VERSION 5.8 ;
BUSBITCHARS "[]" ;
DIVIDERCHAR "/" ;
UNITS
    DATABASE MICRONS 1000 ;
END UNITS

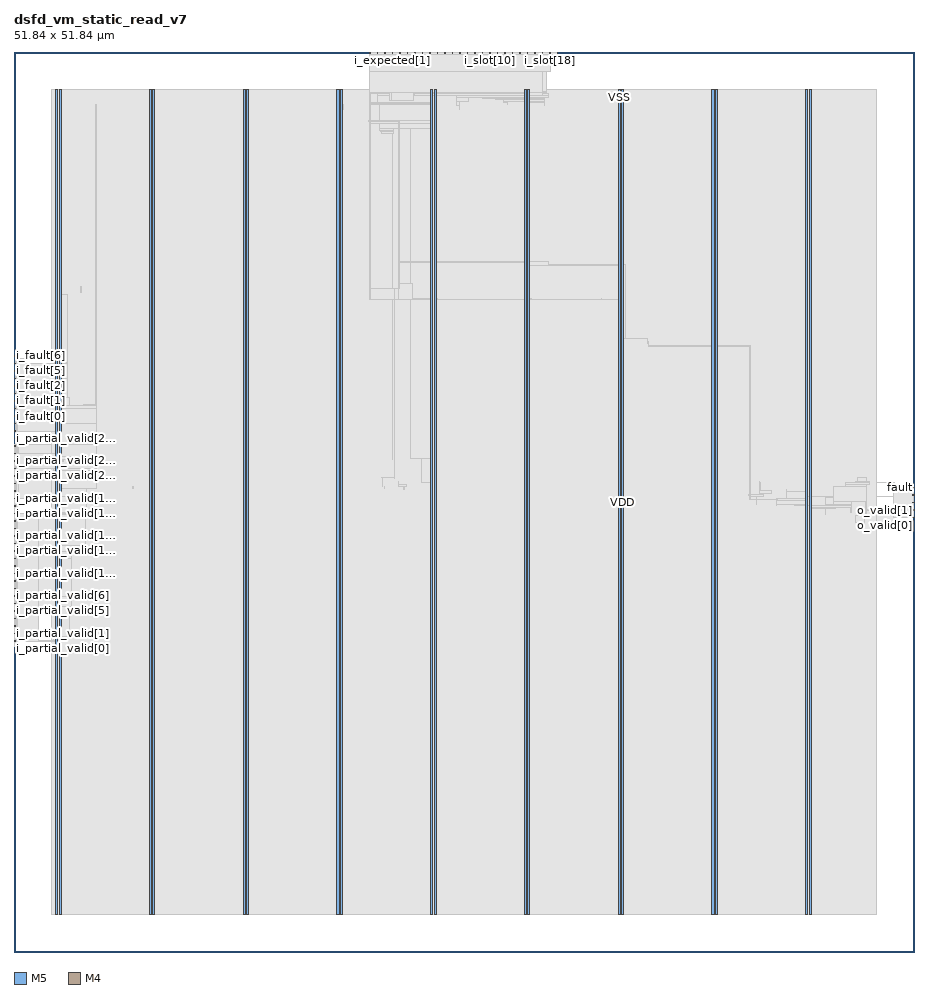
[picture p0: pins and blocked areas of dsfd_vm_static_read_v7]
MACRO dsfd_vm_static_read_v7
  FOREIGN dsfd_vm_static_read_v7 0 0 ;
  CLASS BLOCK ;
  SIZE 51.84 BY 51.84 ;
  PIN ck
    DIRECTION INPUT ;
    USE SIGNAL ;
    PORT
      LAYER M5 ;
        RECT  20.496 51.756 20.52 51.84 ;
    END
  END ck
  PIN fault
    DIRECTION OUTPUT ;
    USE SIGNAL ;
    PORT
      LAYER M4 ;
        RECT  51.756 26.736 51.84 26.76 ;
    END
  END fault
  PIN i_expected[0]
    DIRECTION INPUT ;
    USE SIGNAL ;
    PORT
      LAYER M5 ;
        RECT  21.36 51.756 21.384 51.84 ;
    END
  END i_expected[0]
  PIN i_expected[1]
    DIRECTION INPUT ;
    USE SIGNAL ;
    PORT
      LAYER M5 ;
        RECT  21.792 51.756 21.816 51.84 ;
    END
  END i_expected[1]
  PIN i_expected[2]
    DIRECTION INPUT ;
    USE SIGNAL ;
    PORT
      LAYER M5 ;
        RECT  22.224 51.756 22.248 51.84 ;
    END
  END i_expected[2]
  PIN i_expected[3]
    DIRECTION INPUT ;
    USE SIGNAL ;
    PORT
      LAYER M5 ;
        RECT  22.656 51.756 22.68 51.84 ;
    END
  END i_expected[3]
  PIN i_fault[0]
    DIRECTION INPUT ;
    USE SIGNAL ;
    PORT
      LAYER M4 ;
        RECT  0 31.296 0.084 31.32 ;
    END
  END i_fault[0]
  PIN i_fault[1]
    DIRECTION INPUT ;
    USE SIGNAL ;
    PORT
      LAYER M4 ;
        RECT  0 31.728 0.084 31.752 ;
    END
  END i_fault[1]
  PIN i_fault[2]
    DIRECTION INPUT ;
    USE SIGNAL ;
    PORT
      LAYER M4 ;
        RECT  0 32.16 0.084 32.184 ;
    END
  END i_fault[2]
  PIN i_fault[3]
    DIRECTION INPUT ;
    USE SIGNAL ;
    PORT
      LAYER M4 ;
        RECT  0 32.592 0.084 32.616 ;
    END
  END i_fault[3]
  PIN i_fault[4]
    DIRECTION INPUT ;
    USE SIGNAL ;
    PORT
      LAYER M4 ;
        RECT  0 33.024 0.084 33.048 ;
    END
  END i_fault[4]
  PIN i_fault[5]
    DIRECTION INPUT ;
    USE SIGNAL ;
    PORT
      LAYER M4 ;
        RECT  0 33.456 0.084 33.48 ;
    END
  END i_fault[5]
  PIN i_fault[6]
    DIRECTION INPUT ;
    USE SIGNAL ;
    PORT
      LAYER M4 ;
        RECT  0 33.888 0.084 33.912 ;
    END
  END i_fault[6]
  PIN i_fault[7]
    DIRECTION INPUT ;
    USE SIGNAL ;
    PORT
      LAYER M4 ;
        RECT  0 34.32 0.084 34.344 ;
    END
  END i_fault[7]
  PIN i_partial_valid[0]
    DIRECTION INPUT ;
    USE SIGNAL ;
    PORT
      LAYER M4 ;
        RECT  0 17.472 0.084 17.496 ;
    END
  END i_partial_valid[0]
  PIN i_partial_valid[10]
    DIRECTION INPUT ;
    USE SIGNAL ;
    PORT
      LAYER M4 ;
        RECT  0 21.792 0.084 21.816 ;
    END
  END i_partial_valid[10]
  PIN i_partial_valid[11]
    DIRECTION INPUT ;
    USE SIGNAL ;
    PORT
      LAYER M4 ;
        RECT  0 22.224 0.084 22.248 ;
    END
  END i_partial_valid[11]
  PIN i_partial_valid[12]
    DIRECTION INPUT ;
    USE SIGNAL ;
    PORT
      LAYER M4 ;
        RECT  0 22.656 0.084 22.68 ;
    END
  END i_partial_valid[12]
  PIN i_partial_valid[13]
    DIRECTION INPUT ;
    USE SIGNAL ;
    PORT
      LAYER M4 ;
        RECT  0 23.088 0.084 23.112 ;
    END
  END i_partial_valid[13]
  PIN i_partial_valid[14]
    DIRECTION INPUT ;
    USE SIGNAL ;
    PORT
      LAYER M4 ;
        RECT  0 23.52 0.084 23.544 ;
    END
  END i_partial_valid[14]
  PIN i_partial_valid[15]
    DIRECTION INPUT ;
    USE SIGNAL ;
    PORT
      LAYER M4 ;
        RECT  0 23.952 0.084 23.976 ;
    END
  END i_partial_valid[15]
  PIN i_partial_valid[16]
    DIRECTION INPUT ;
    USE SIGNAL ;
    PORT
      LAYER M4 ;
        RECT  0 24.384 0.084 24.408 ;
    END
  END i_partial_valid[16]
  PIN i_partial_valid[17]
    DIRECTION INPUT ;
    USE SIGNAL ;
    PORT
      LAYER M4 ;
        RECT  0 24.816 0.084 24.84 ;
    END
  END i_partial_valid[17]
  PIN i_partial_valid[18]
    DIRECTION INPUT ;
    USE SIGNAL ;
    PORT
      LAYER M4 ;
        RECT  0 25.248 0.084 25.272 ;
    END
  END i_partial_valid[18]
  PIN i_partial_valid[19]
    DIRECTION INPUT ;
    USE SIGNAL ;
    PORT
      LAYER M4 ;
        RECT  0 25.68 0.084 25.704 ;
    END
  END i_partial_valid[19]
  PIN i_partial_valid[1]
    DIRECTION INPUT ;
    USE SIGNAL ;
    PORT
      LAYER M4 ;
        RECT  0 17.904 0.084 17.928 ;
    END
  END i_partial_valid[1]
  PIN i_partial_valid[20]
    DIRECTION INPUT ;
    USE SIGNAL ;
    PORT
      LAYER M4 ;
        RECT  0 26.112 0.084 26.136 ;
    END
  END i_partial_valid[20]
  PIN i_partial_valid[21]
    DIRECTION INPUT ;
    USE SIGNAL ;
    PORT
      LAYER M4 ;
        RECT  0 26.544 0.084 26.568 ;
    END
  END i_partial_valid[21]
  PIN i_partial_valid[22]
    DIRECTION INPUT ;
    USE SIGNAL ;
    PORT
      LAYER M4 ;
        RECT  0 26.976 0.084 27 ;
    END
  END i_partial_valid[22]
  PIN i_partial_valid[23]
    DIRECTION INPUT ;
    USE SIGNAL ;
    PORT
      LAYER M4 ;
        RECT  0 27.408 0.084 27.432 ;
    END
  END i_partial_valid[23]
  PIN i_partial_valid[24]
    DIRECTION INPUT ;
    USE SIGNAL ;
    PORT
      LAYER M4 ;
        RECT  0 27.84 0.084 27.864 ;
    END
  END i_partial_valid[24]
  PIN i_partial_valid[25]
    DIRECTION INPUT ;
    USE SIGNAL ;
    PORT
      LAYER M4 ;
        RECT  0 28.272 0.084 28.296 ;
    END
  END i_partial_valid[25]
  PIN i_partial_valid[26]
    DIRECTION INPUT ;
    USE SIGNAL ;
    PORT
      LAYER M4 ;
        RECT  0 28.704 0.084 28.728 ;
    END
  END i_partial_valid[26]
  PIN i_partial_valid[27]
    DIRECTION INPUT ;
    USE SIGNAL ;
    PORT
      LAYER M4 ;
        RECT  0 29.136 0.084 29.16 ;
    END
  END i_partial_valid[27]
  PIN i_partial_valid[28]
    DIRECTION INPUT ;
    USE SIGNAL ;
    PORT
      LAYER M4 ;
        RECT  0 29.568 0.084 29.592 ;
    END
  END i_partial_valid[28]
  PIN i_partial_valid[29]
    DIRECTION INPUT ;
    USE SIGNAL ;
    PORT
      LAYER M4 ;
        RECT  0 30 0.084 30.024 ;
    END
  END i_partial_valid[29]
  PIN i_partial_valid[2]
    DIRECTION INPUT ;
    USE SIGNAL ;
    PORT
      LAYER M4 ;
        RECT  0 18.336 0.084 18.36 ;
    END
  END i_partial_valid[2]
  PIN i_partial_valid[30]
    DIRECTION INPUT ;
    USE SIGNAL ;
    PORT
      LAYER M4 ;
        RECT  0 30.432 0.084 30.456 ;
    END
  END i_partial_valid[30]
  PIN i_partial_valid[31]
    DIRECTION INPUT ;
    USE SIGNAL ;
    PORT
      LAYER M4 ;
        RECT  0 30.864 0.084 30.888 ;
    END
  END i_partial_valid[31]
  PIN i_partial_valid[3]
    DIRECTION INPUT ;
    USE SIGNAL ;
    PORT
      LAYER M4 ;
        RECT  0 18.768 0.084 18.792 ;
    END
  END i_partial_valid[3]
  PIN i_partial_valid[4]
    DIRECTION INPUT ;
    USE SIGNAL ;
    PORT
      LAYER M4 ;
        RECT  0 19.2 0.084 19.224 ;
    END
  END i_partial_valid[4]
  PIN i_partial_valid[5]
    DIRECTION INPUT ;
    USE SIGNAL ;
    PORT
      LAYER M4 ;
        RECT  0 19.632 0.084 19.656 ;
    END
  END i_partial_valid[5]
  PIN i_partial_valid[6]
    DIRECTION INPUT ;
    USE SIGNAL ;
    PORT
      LAYER M4 ;
        RECT  0 20.064 0.084 20.088 ;
    END
  END i_partial_valid[6]
  PIN i_partial_valid[7]
    DIRECTION INPUT ;
    USE SIGNAL ;
    PORT
      LAYER M4 ;
        RECT  0 20.496 0.084 20.52 ;
    END
  END i_partial_valid[7]
  PIN i_partial_valid[8]
    DIRECTION INPUT ;
    USE SIGNAL ;
    PORT
      LAYER M4 ;
        RECT  0 20.928 0.084 20.952 ;
    END
  END i_partial_valid[8]
  PIN i_partial_valid[9]
    DIRECTION INPUT ;
    USE SIGNAL ;
    PORT
      LAYER M4 ;
        RECT  0 21.36 0.084 21.384 ;
    END
  END i_partial_valid[9]
  PIN i_slot[0]
    DIRECTION INPUT ;
    USE SIGNAL ;
    PORT
      LAYER M5 ;
        RECT  23.088 51.756 23.112 51.84 ;
    END
  END i_slot[0]
  PIN i_slot[10]
    DIRECTION INPUT ;
    USE SIGNAL ;
    PORT
      LAYER M5 ;
        RECT  27.408 51.756 27.432 51.84 ;
    END
  END i_slot[10]
  PIN i_slot[11]
    DIRECTION INPUT ;
    USE SIGNAL ;
    PORT
      LAYER M5 ;
        RECT  27.84 51.756 27.864 51.84 ;
    END
  END i_slot[11]
  PIN i_slot[12]
    DIRECTION INPUT ;
    USE SIGNAL ;
    PORT
      LAYER M5 ;
        RECT  28.272 51.756 28.296 51.84 ;
    END
  END i_slot[12]
  PIN i_slot[13]
    DIRECTION INPUT ;
    USE SIGNAL ;
    PORT
      LAYER M5 ;
        RECT  28.704 51.756 28.728 51.84 ;
    END
  END i_slot[13]
  PIN i_slot[14]
    DIRECTION INPUT ;
    USE SIGNAL ;
    PORT
      LAYER M5 ;
        RECT  29.136 51.756 29.16 51.84 ;
    END
  END i_slot[14]
  PIN i_slot[15]
    DIRECTION INPUT ;
    USE SIGNAL ;
    PORT
      LAYER M5 ;
        RECT  29.568 51.756 29.592 51.84 ;
    END
  END i_slot[15]
  PIN i_slot[16]
    DIRECTION INPUT ;
    USE SIGNAL ;
    PORT
      LAYER M5 ;
        RECT  30 51.756 30.024 51.84 ;
    END
  END i_slot[16]
  PIN i_slot[17]
    DIRECTION INPUT ;
    USE SIGNAL ;
    PORT
      LAYER M5 ;
        RECT  30.432 51.756 30.456 51.84 ;
    END
  END i_slot[17]
  PIN i_slot[18]
    DIRECTION INPUT ;
    USE SIGNAL ;
    PORT
      LAYER M5 ;
        RECT  30.864 51.756 30.888 51.84 ;
    END
  END i_slot[18]
  PIN i_slot[19]
    DIRECTION INPUT ;
    USE SIGNAL ;
    PORT
      LAYER M5 ;
        RECT  31.296 51.756 31.32 51.84 ;
    END
  END i_slot[19]
  PIN i_slot[1]
    DIRECTION INPUT ;
    USE SIGNAL ;
    PORT
      LAYER M5 ;
        RECT  23.52 51.756 23.544 51.84 ;
    END
  END i_slot[1]
  PIN i_slot[2]
    DIRECTION INPUT ;
    USE SIGNAL ;
    PORT
      LAYER M5 ;
        RECT  23.952 51.756 23.976 51.84 ;
    END
  END i_slot[2]
  PIN i_slot[3]
    DIRECTION INPUT ;
    USE SIGNAL ;
    PORT
      LAYER M5 ;
        RECT  24.384 51.756 24.408 51.84 ;
    END
  END i_slot[3]
  PIN i_slot[4]
    DIRECTION INPUT ;
    USE SIGNAL ;
    PORT
      LAYER M5 ;
        RECT  24.816 51.756 24.84 51.84 ;
    END
  END i_slot[4]
  PIN i_slot[5]
    DIRECTION INPUT ;
    USE SIGNAL ;
    PORT
      LAYER M5 ;
        RECT  25.248 51.756 25.272 51.84 ;
    END
  END i_slot[5]
  PIN i_slot[6]
    DIRECTION INPUT ;
    USE SIGNAL ;
    PORT
      LAYER M5 ;
        RECT  25.68 51.756 25.704 51.84 ;
    END
  END i_slot[6]
  PIN i_slot[7]
    DIRECTION INPUT ;
    USE SIGNAL ;
    PORT
      LAYER M5 ;
        RECT  26.112 51.756 26.136 51.84 ;
    END
  END i_slot[7]
  PIN i_slot[8]
    DIRECTION INPUT ;
    USE SIGNAL ;
    PORT
      LAYER M5 ;
        RECT  26.544 51.756 26.568 51.84 ;
    END
  END i_slot[8]
  PIN i_slot[9]
    DIRECTION INPUT ;
    USE SIGNAL ;
    PORT
      LAYER M5 ;
        RECT  26.976 51.756 27 51.84 ;
    END
  END i_slot[9]
  PIN o_valid[0]
    DIRECTION OUTPUT ;
    USE SIGNAL ;
    PORT
      LAYER M4 ;
        RECT  51.756 25.008 51.84 25.032 ;
    END
  END o_valid[0]
  PIN o_valid[1]
    DIRECTION OUTPUT ;
    USE SIGNAL ;
    PORT
      LAYER M4 ;
        RECT  51.756 25.44 51.84 25.464 ;
    END
  END o_valid[1]
  PIN o_valid[2]
    DIRECTION OUTPUT ;
    USE SIGNAL ;
    PORT
      LAYER M4 ;
        RECT  51.756 25.872 51.84 25.896 ;
    END
  END o_valid[2]
  PIN o_valid[3]
    DIRECTION OUTPUT ;
    USE SIGNAL ;
    PORT
      LAYER M4 ;
        RECT  51.756 26.304 51.84 26.328 ;
    END
  END o_valid[3]
  PIN rst_n
    DIRECTION INPUT ;
    USE SIGNAL ;
    PORT
      LAYER M5 ;
        RECT  20.928 51.756 20.952 51.84 ;
    END
  END rst_n
  PIN VDD
    DIRECTION INOUT ;
    USE POWER ;
    PORT
      LAYER M5 ;
        RECT  45.792 2.151 45.912 49.689 ;
        RECT  40.392 2.151 40.512 49.689 ;
        RECT  34.992 2.151 35.112 49.689 ;
        RECT  29.592 2.151 29.712 49.689 ;
        RECT  24.192 2.151 24.312 49.689 ;
        RECT  18.792 2.151 18.912 49.689 ;
        RECT  13.392 2.151 13.512 49.689 ;
        RECT  7.992 2.151 8.112 49.689 ;
        RECT  2.592 2.151 2.712 49.689 ;
    END
  END VDD
  PIN VSS
    DIRECTION INOUT ;
    USE GROUND ;
    PORT
      LAYER M5 ;
        RECT  45.6 2.137 45.72 49.703 ;
        RECT  40.2 2.137 40.32 49.703 ;
        RECT  34.8 2.137 34.92 49.703 ;
        RECT  29.4 2.137 29.52 49.703 ;
        RECT  24 2.137 24.12 49.703 ;
        RECT  18.6 2.137 18.72 49.703 ;
        RECT  13.2 2.137 13.32 49.703 ;
        RECT  7.8 2.137 7.92 49.703 ;
        RECT  2.4 2.137 2.52 49.703 ;
    END
  END VSS
  # OT_OBS_CLOSED layer=M5 d_um=1.536 added=1
  OBS
    LAYER RVTN ;
     RECT  2.16 2.16 49.68 2.295 ;
     RECT  2.16 2.565 49.68 2.835 ;
     RECT  2.16 3.105 49.68 3.375 ;
     RECT  2.16 3.645 49.68 3.915 ;
     RECT  2.16 4.185 49.68 4.455 ;
     RECT  2.16 4.725 49.68 4.995 ;
     RECT  2.16 5.265 49.68 5.535 ;
     RECT  2.16 5.805 49.68 6.075 ;
     RECT  2.16 6.345 49.68 6.615 ;
     RECT  2.16 6.885 49.68 7.155 ;
     RECT  2.16 7.425 49.68 7.695 ;
     RECT  2.16 7.965 49.68 8.235 ;
     RECT  2.16 8.505 49.68 8.775 ;
     RECT  2.16 9.045 49.68 9.315 ;
     RECT  2.16 9.585 49.68 9.855 ;
     RECT  2.16 10.125 49.68 10.395 ;
     RECT  2.16 10.665 49.68 10.935 ;
     RECT  2.16 11.205 49.68 11.475 ;
     RECT  2.16 11.745 49.68 12.015 ;
     RECT  2.16 12.285 49.68 12.555 ;
     RECT  2.16 12.825 49.68 13.095 ;
     RECT  2.16 13.365 49.68 13.635 ;
     RECT  2.16 13.905 49.68 14.175 ;
     RECT  2.16 14.445 49.68 14.715 ;
     RECT  2.16 14.985 49.68 15.255 ;
     RECT  2.16 15.525 49.68 15.795 ;
     RECT  2.16 16.065 49.68 16.335 ;
     RECT  2.16 16.605 49.68 16.875 ;
     RECT  2.16 17.145 49.68 17.415 ;
     RECT  2.16 17.685 49.68 17.955 ;
     RECT  2.16 18.225 49.68 18.495 ;
     RECT  2.16 18.765 49.68 19.035 ;
     RECT  2.16 19.305 49.68 19.575 ;
     RECT  2.16 19.845 49.68 20.115 ;
     RECT  2.16 20.385 49.68 20.655 ;
     RECT  2.16 20.925 49.68 21.195 ;
     RECT  2.16 21.465 49.68 21.735 ;
     RECT  2.16 22.005 49.68 22.275 ;
     RECT  2.16 22.545 49.68 22.815 ;
     RECT  2.16 23.085 49.68 23.355 ;
     RECT  2.16 23.625 49.68 23.895 ;
     RECT  2.16 24.165 49.68 24.435 ;
     RECT  2.16 24.705 49.68 24.975 ;
     RECT  2.16 25.245 49.68 25.515 ;
     RECT  2.16 25.785 49.68 26.055 ;
     RECT  2.16 26.325 49.68 26.595 ;
     RECT  2.16 26.865 49.68 27.135 ;
     RECT  2.16 27.405 49.68 27.675 ;
     RECT  2.16 27.945 49.68 28.215 ;
     RECT  2.16 28.485 49.68 28.755 ;
     RECT  2.16 29.025 49.68 29.295 ;
     RECT  2.16 29.565 49.68 29.835 ;
     RECT  2.16 30.105 49.68 30.375 ;
     RECT  2.16 30.645 49.68 30.915 ;
     RECT  2.16 31.185 49.68 31.455 ;
     RECT  2.16 31.725 49.68 31.995 ;
     RECT  2.16 32.265 49.68 32.535 ;
     RECT  2.16 32.805 49.68 33.075 ;
     RECT  2.16 33.345 49.68 33.615 ;
     RECT  2.16 33.885 49.68 34.155 ;
     RECT  2.16 34.425 49.68 34.695 ;
     RECT  2.16 34.965 49.68 35.235 ;
     RECT  2.16 35.505 49.68 35.775 ;
     RECT  2.16 36.045 49.68 36.315 ;
     RECT  2.16 36.585 49.68 36.855 ;
     RECT  2.16 37.125 49.68 37.395 ;
     RECT  2.16 37.665 49.68 37.935 ;
     RECT  2.16 38.205 49.68 38.475 ;
     RECT  2.16 38.745 49.68 39.015 ;
     RECT  2.16 39.285 49.68 39.555 ;
     RECT  2.16 39.825 49.68 40.095 ;
     RECT  2.16 40.365 49.68 40.635 ;
     RECT  2.16 40.905 49.68 41.175 ;
     RECT  2.16 41.445 49.68 41.715 ;
     RECT  2.16 41.985 49.68 42.255 ;
     RECT  2.16 42.525 49.68 42.795 ;
     RECT  2.16 43.065 49.68 43.335 ;
     RECT  2.16 43.605 49.68 43.875 ;
     RECT  2.16 44.145 49.68 44.415 ;
     RECT  2.16 44.685 49.68 44.955 ;
     RECT  2.16 45.225 49.68 45.495 ;
     RECT  2.16 45.765 49.68 46.035 ;
     RECT  2.16 46.305 49.68 46.575 ;
     RECT  2.16 46.845 49.68 47.115 ;
     RECT  2.16 47.385 49.68 47.655 ;
     RECT  2.16 47.925 49.68 48.195 ;
     RECT  2.16 48.465 49.68 48.735 ;
     RECT  2.16 49.005 49.68 49.275 ;
     RECT  2.16 49.545 49.68 49.68 ;
    LAYER RVTP ;
     RECT  2.16 2.295 49.68 2.565 ;
     RECT  2.16 2.835 49.68 3.105 ;
     RECT  2.16 3.375 49.68 3.645 ;
     RECT  2.16 3.915 49.68 4.185 ;
     RECT  2.16 4.455 49.68 4.725 ;
     RECT  2.16 4.995 49.68 5.265 ;
     RECT  2.16 5.535 49.68 5.805 ;
     RECT  2.16 6.075 49.68 6.345 ;
     RECT  2.16 6.615 49.68 6.885 ;
     RECT  2.16 7.155 49.68 7.425 ;
     RECT  2.16 7.695 49.68 7.965 ;
     RECT  2.16 8.235 49.68 8.505 ;
     RECT  2.16 8.775 49.68 9.045 ;
     RECT  2.16 9.315 49.68 9.585 ;
     RECT  2.16 9.855 49.68 10.125 ;
     RECT  2.16 10.395 49.68 10.665 ;
     RECT  2.16 10.935 49.68 11.205 ;
     RECT  2.16 11.475 49.68 11.745 ;
     RECT  2.16 12.015 49.68 12.285 ;
     RECT  2.16 12.555 49.68 12.825 ;
     RECT  2.16 13.095 49.68 13.365 ;
     RECT  2.16 13.635 49.68 13.905 ;
     RECT  2.16 14.175 49.68 14.445 ;
     RECT  2.16 14.715 49.68 14.985 ;
     RECT  2.16 15.255 49.68 15.525 ;
     RECT  2.16 15.795 49.68 16.065 ;
     RECT  2.16 16.335 49.68 16.605 ;
     RECT  2.16 16.875 49.68 17.145 ;
     RECT  2.16 17.415 49.68 17.685 ;
     RECT  2.16 17.955 49.68 18.225 ;
     RECT  2.16 18.495 49.68 18.765 ;
     RECT  2.16 19.035 49.68 19.305 ;
     RECT  2.16 19.575 49.68 19.845 ;
     RECT  2.16 20.115 49.68 20.385 ;
     RECT  2.16 20.655 49.68 20.925 ;
     RECT  2.16 21.195 49.68 21.465 ;
     RECT  2.16 21.735 49.68 22.005 ;
     RECT  2.16 22.275 49.68 22.545 ;
     RECT  2.16 22.815 49.68 23.085 ;
     RECT  2.16 23.355 49.68 23.625 ;
     RECT  2.16 23.895 49.68 24.165 ;
     RECT  2.16 24.435 49.68 24.705 ;
     RECT  2.16 24.975 49.68 25.245 ;
     RECT  2.16 25.515 49.68 25.785 ;
     RECT  2.16 26.055 49.68 26.325 ;
     RECT  2.16 26.595 49.68 26.865 ;
     RECT  2.16 27.135 49.68 27.405 ;
     RECT  2.16 27.675 49.68 27.945 ;
     RECT  2.16 28.215 49.68 28.485 ;
     RECT  2.16 28.755 49.68 29.025 ;
     RECT  2.16 29.295 49.68 29.565 ;
     RECT  2.16 29.835 49.68 30.105 ;
     RECT  2.16 30.375 49.68 30.645 ;
     RECT  2.16 30.915 49.68 31.185 ;
     RECT  2.16 31.455 49.68 31.725 ;
     RECT  2.16 31.995 49.68 32.265 ;
     RECT  2.16 32.535 49.68 32.805 ;
     RECT  2.16 33.075 49.68 33.345 ;
     RECT  2.16 33.615 49.68 33.885 ;
     RECT  2.16 34.155 49.68 34.425 ;
     RECT  2.16 34.695 49.68 34.965 ;
     RECT  2.16 35.235 49.68 35.505 ;
     RECT  2.16 35.775 49.68 36.045 ;
     RECT  2.16 36.315 49.68 36.585 ;
     RECT  2.16 36.855 49.68 37.125 ;
     RECT  2.16 37.395 49.68 37.665 ;
     RECT  2.16 37.935 49.68 38.205 ;
     RECT  2.16 38.475 49.68 38.745 ;
     RECT  2.16 39.015 49.68 39.285 ;
     RECT  2.16 39.555 49.68 39.825 ;
     RECT  2.16 40.095 49.68 40.365 ;
     RECT  2.16 40.635 49.68 40.905 ;
     RECT  2.16 41.175 49.68 41.445 ;
     RECT  2.16 41.715 49.68 41.985 ;
     RECT  2.16 42.255 49.68 42.525 ;
     RECT  2.16 42.795 49.68 43.065 ;
     RECT  2.16 43.335 49.68 43.605 ;
     RECT  2.16 43.875 49.68 44.145 ;
     RECT  2.16 44.415 49.68 44.685 ;
     RECT  2.16 44.955 49.68 45.225 ;
     RECT  2.16 45.495 49.68 45.765 ;
     RECT  2.16 46.035 49.68 46.305 ;
     RECT  2.16 46.575 49.68 46.845 ;
     RECT  2.16 47.115 49.68 47.385 ;
     RECT  2.16 47.655 49.68 47.925 ;
     RECT  2.16 48.195 49.68 48.465 ;
     RECT  2.16 48.735 49.68 49.005 ;
     RECT  2.16 49.275 49.68 49.545 ;
    LAYER M1 ;
     RECT  2.16 2.151 49.68 49.689 ;
    LAYER M2 ;
     RECT  0.031 29.232 0.103 29.25 ;
     RECT  0.103 22.896 0.139 22.914 ;
     RECT  0.103 23.67 0.139 23.688 ;
     RECT  0.103 26.136 0.211 26.784 ;
     RECT  0.067 27.882 0.211 27.9 ;
     RECT  0.139 22.824 0.239 23.688 ;
     RECT  0.211 26.136 0.247 27.9 ;
     RECT  0.103 28.8 0.247 29.25 ;
     RECT  0.239 22.896 0.275 23.688 ;
     RECT  1.399 20.592 2.16 20.61 ;
     RECT  0.275 23.292 2.16 23.688 ;
     RECT  0.103 25.02 2.16 25.038 ;
     RECT  0.247 26.136 2.16 29.25 ;
     RECT  0.103 32.472 2.16 33.066 ;
     RECT  0.103 34.164 2.16 34.182 ;
     RECT  2.16 2.151 49.68 49.689 ;
     RECT  49.68 24.786 50.711 25.47 ;
     RECT  49.68 26.226 50.711 26.244 ;
     RECT  49.68 27.036 50.711 27.054 ;
     RECT  50.711 25.326 50.747 25.344 ;
    LAYER M3 ;
     RECT  2.415 2.143 2.505 2.413 ;
     RECT  7.815 2.143 7.905 2.413 ;
     RECT  13.215 2.143 13.305 2.413 ;
     RECT  18.615 2.143 18.705 2.413 ;
     RECT  24.015 2.143 24.105 2.413 ;
     RECT  29.415 2.143 29.505 2.413 ;
     RECT  34.815 2.143 34.905 2.413 ;
     RECT  40.215 2.143 40.305 2.413 ;
     RECT  45.615 2.143 45.705 2.413 ;
     RECT  0.108 17.467 0.126 17.611 ;
     RECT  2.415 2.413 2.697 17.899 ;
     RECT  2.304 17.899 2.697 18.185 ;
     RECT  2.415 18.185 2.697 18.193 ;
     RECT  0.036 17.611 0.126 18.331 ;
     RECT  0.036 18.331 0.162 18.461 ;
     RECT  0.036 18.461 0.09 19.195 ;
     RECT  2.415 18.193 3.222 19.921 ;
     RECT  2.415 19.921 3.33 20.491 ;
     RECT  1.404 18.763 1.422 20.615 ;
     RECT  2.304 20.491 3.33 22.651 ;
     RECT  0.036 19.195 0.162 22.819 ;
     RECT  0.036 22.819 0.234 22.891 ;
     RECT  2.268 22.651 3.33 23.045 ;
     RECT  2.304 23.045 3.33 23.395 ;
     RECT  4.104 23.251 4.122 23.395 ;
     RECT  48.996 24.601 49.014 24.745 ;
     RECT  48.456 24.745 49.014 25.169 ;
     RECT  2.304 23.395 4.122 25.205 ;
     RECT  2.376 25.205 4.122 25.285 ;
     RECT  2.376 25.285 4.158 25.321 ;
     RECT  50.688 24.781 50.706 25.321 ;
     RECT  49.032 25.285 49.086 25.411 ;
     RECT  50.688 25.321 50.742 25.475 ;
     RECT  49.032 25.411 49.338 25.511 ;
     RECT  46.728 25.177 46.746 25.519 ;
     RECT  45.615 2.413 45.897 25.555 ;
     RECT  46.728 25.519 47.214 25.555 ;
     RECT  45.615 25.555 47.322 25.591 ;
     RECT  48.204 25.321 48.222 25.591 ;
     RECT  45.615 25.591 48.222 25.717 ;
     RECT  43.92 25.717 43.938 25.753 ;
     RECT  44.964 25.717 48.222 25.753 ;
     RECT  43.92 25.753 48.222 25.757 ;
     RECT  50.724 25.475 50.742 25.901 ;
     RECT  47.196 25.757 48.222 25.951 ;
     RECT  49.032 25.511 49.086 25.951 ;
     RECT  43.92 25.757 46.242 26.015 ;
     RECT  43.92 26.015 45.897 26.093 ;
     RECT  2.376 25.321 4.194 26.249 ;
     RECT  42.768 25.753 42.786 26.257 ;
     RECT  42.372 26.257 43.182 26.333 ;
     RECT  42.912 26.333 43.182 26.401 ;
     RECT  44.496 26.093 45.897 26.519 ;
     RECT  42.912 26.401 43.65 26.555 ;
     RECT  44.496 26.519 44.514 26.627 ;
     RECT  2.415 26.249 4.194 26.671 ;
     RECT  6.84 26.671 6.858 26.789 ;
     RECT  21.348 26.671 21.366 26.789 ;
     RECT  47.196 25.951 49.086 26.789 ;
     RECT  22.464 26.635 22.482 26.797 ;
     RECT  22.284 26.797 22.626 26.833 ;
     RECT  22.14 26.833 22.626 26.933 ;
     RECT  47.88 26.789 49.086 26.941 ;
     RECT  42.912 26.555 43.002 27.059 ;
     RECT  47.88 26.941 49.302 27.059 ;
     RECT  50.688 26.221 50.706 27.059 ;
     RECT  24.015 2.413 24.297 27.067 ;
     RECT  22.14 26.933 22.158 27.095 ;
     RECT  42.912 27.059 42.93 27.095 ;
     RECT  48.456 27.059 49.302 27.095 ;
     RECT  2.415 26.671 4.734 27.211 ;
     RECT  48.564 27.095 49.086 27.329 ;
     RECT  21.204 26.797 21.222 27.341 ;
     RECT  2.376 27.211 4.734 27.751 ;
     RECT  2.304 27.751 4.734 27.869 ;
     RECT  0.036 22.891 0.27 28.175 ;
     RECT  2.376 27.869 4.734 28.381 ;
     RECT  23.472 27.067 24.297 28.453 ;
     RECT  2.376 28.381 5.13 28.517 ;
     RECT  0.036 28.175 0.126 29.029 ;
     RECT  2.376 28.517 4.734 29.219 ;
     RECT  0.036 29.029 0.162 29.255 ;
     RECT  0.144 29.255 0.162 29.597 ;
     RECT  2.415 29.219 4.734 30.415 ;
     RECT  2.304 30.415 4.734 30.461 ;
     RECT  2.415 30.461 4.734 31.291 ;
     RECT  2.304 31.291 4.734 31.487 ;
     RECT  3.996 31.487 4.734 31.559 ;
     RECT  2.304 31.487 3.222 31.919 ;
     RECT  2.304 31.919 3.078 33.053 ;
     RECT  2.415 33.053 3.078 33.883 ;
     RECT  2.304 33.883 3.078 33.953 ;
     RECT  0.108 32.467 0.126 34.349 ;
     RECT  37.584 34.861 37.602 34.925 ;
     RECT  36.54 34.891 36.558 35.041 ;
     RECT  36.468 35.041 36.558 35.159 ;
     RECT  36.468 35.159 36.486 35.357 ;
     RECT  22.86 28.453 24.297 37.579 ;
     RECT  29.415 2.413 29.697 37.579 ;
     RECT  34.815 2.413 35.097 37.579 ;
     RECT  33.84 37.561 33.858 37.613 ;
     RECT  22.86 37.579 24.39 37.625 ;
     RECT  29.415 37.579 29.79 37.625 ;
     RECT  34.815 37.579 35.19 37.625 ;
     RECT  2.415 33.953 3.078 37.859 ;
     RECT  3.852 38.011 3.87 38.309 ;
     RECT  30.492 39.547 30.51 39.721 ;
     RECT  30.492 39.721 30.798 39.749 ;
     RECT  30.78 39.749 30.798 39.773 ;
     RECT  21.78 28.381 21.798 47.155 ;
     RECT  21.168 47.155 21.834 47.281 ;
     RECT  21.132 47.281 21.834 47.317 ;
     RECT  21.024 47.317 21.87 47.461 ;
     RECT  22.86 37.625 24.297 47.461 ;
     RECT  21.024 47.461 24.297 47.695 ;
     RECT  20.448 47.695 24.297 47.885 ;
     RECT  18.615 2.413 18.897 48.541 ;
     RECT  25.668 48.541 25.686 48.775 ;
     RECT  21.024 47.885 24.297 48.811 ;
     RECT  4.716 31.559 4.734 48.839 ;
     RECT  18.615 48.541 18.954 48.839 ;
     RECT  20.52 48.811 24.297 48.901 ;
     RECT  20.52 48.901 24.354 48.929 ;
     RECT  28.404 48.811 28.422 48.937 ;
     RECT  29.415 37.625 29.697 48.937 ;
     RECT  30.564 48.775 30.582 48.937 ;
     RECT  25.488 48.775 25.686 48.973 ;
     RECT  28.188 48.937 28.422 48.973 ;
     RECT  29.415 48.937 30.582 48.973 ;
     RECT  28.188 48.973 30.582 49.081 ;
     RECT  27.72 49.081 30.582 49.171 ;
     RECT  25.488 48.973 26.19 49.207 ;
     RECT  27 49.171 30.582 49.207 ;
     RECT  25.488 49.207 30.582 49.243 ;
     RECT  20.916 48.929 24.354 49.315 ;
     RECT  25.488 49.243 30.798 49.315 ;
     RECT  2.415 37.859 2.697 49.427 ;
     RECT  7.815 2.413 8.097 49.427 ;
     RECT  13.215 2.413 13.497 49.427 ;
     RECT  18.615 48.839 18.897 49.427 ;
     RECT  34.815 37.625 35.097 49.427 ;
     RECT  40.215 2.413 40.497 49.427 ;
     RECT  45.615 26.519 45.897 49.427 ;
     RECT  20.916 49.315 30.798 49.469 ;
     RECT  20.988 49.469 22.662 49.517 ;
     RECT  25.416 49.469 30.654 49.517 ;
     RECT  23.508 49.469 24.678 49.565 ;
     RECT  25.668 49.517 26.874 49.565 ;
     RECT  27.828 49.517 30.654 49.565 ;
     RECT  21.096 49.517 22.662 49.577 ;
     RECT  23.508 49.565 24.105 49.577 ;
     RECT  25.668 49.565 26.01 49.577 ;
     RECT  26.856 49.565 26.874 49.577 ;
     RECT  27.828 49.565 27.846 49.577 ;
     RECT  28.584 49.565 30.654 49.577 ;
     RECT  2.415 49.427 2.505 49.697 ;
     RECT  7.815 49.427 7.905 49.697 ;
     RECT  13.215 49.427 13.305 49.697 ;
     RECT  18.615 49.427 18.705 49.697 ;
     RECT  23.832 49.577 24.105 49.697 ;
     RECT  34.815 49.427 34.905 49.697 ;
     RECT  40.215 49.427 40.305 49.697 ;
     RECT  45.615 49.427 45.705 49.697 ;
     RECT  28.98 49.577 29.61 49.805 ;
     RECT  22.212 49.577 22.23 50.765 ;
     RECT  23.832 49.697 23.85 50.765 ;
     RECT  28.98 49.805 28.998 50.765 ;
     RECT  30.384 49.577 30.654 50.765 ;
     RECT  30.384 50.765 30.402 51.725 ;
    LAYER M4 ;
     RECT  0.025 17.616 0.06 17.64 ;
     RECT  0.06 17.472 0.137 34.344 ;
     RECT  0.137 17.904 0.173 26.136 ;
     RECT  0.137 27.408 0.173 33.912 ;
     RECT  0.173 17.904 1.433 25.272 ;
     RECT  1.433 17.904 2.408 17.928 ;
     RECT  1.433 19.632 2.408 25.272 ;
     RECT  0.173 27.84 2.408 28.728 ;
     RECT  0.173 30 2.408 33.912 ;
     RECT  2.408 2.148 2.512 49.692 ;
     RECT  2.512 2.418 2.704 49.422 ;
     RECT  2.704 28.272 2.837 28.296 ;
     RECT  7.808 2.148 7.912 49.692 ;
     RECT  7.912 2.418 8.104 49.422 ;
     RECT  13.208 2.148 13.312 49.692 ;
     RECT  13.312 2.418 13.504 49.422 ;
     RECT  18.608 2.148 18.712 49.692 ;
     RECT  18.712 2.418 18.904 49.422 ;
     RECT  20.917 49.488 21.625 49.512 ;
     RECT  21.625 49.056 21.74 49.512 ;
     RECT  20.485 37.584 21.877 37.608 ;
     RECT  21.193 27.312 21.923 27.336 ;
     RECT  21.877 37.584 22.165 38.232 ;
     RECT  20.437 47.856 22.211 47.88 ;
     RECT  22.172 50.736 22.259 50.76 ;
     RECT  22.165 37.584 22.961 38.52 ;
     RECT  21.74 49.056 23.033 49.56 ;
     RECT  23.821 50.736 23.987 50.76 ;
     RECT  22.961 37.584 24.008 37.608 ;
     RECT  22.165 39.744 24.008 39.768 ;
     RECT  23.033 49.344 24.008 49.56 ;
     RECT  24.008 2.148 24.112 49.692 ;
     RECT  24.112 2.418 24.304 49.56 ;
     RECT  24.304 49.488 25.445 49.56 ;
     RECT  25.445 49.536 27.397 49.56 ;
     RECT  27.397 49.488 27.605 49.56 ;
     RECT  28.969 50.736 29.171 50.76 ;
     RECT  24.304 37.584 29.408 37.608 ;
     RECT  24.304 39.744 29.408 39.768 ;
     RECT  27.605 49.536 29.408 49.56 ;
     RECT  29.408 2.148 29.512 49.692 ;
     RECT  29.512 2.418 29.557 49.692 ;
     RECT  29.557 2.418 29.644 49.8 ;
     RECT  29.644 2.418 29.704 49.56 ;
     RECT  29.704 49.344 30.125 49.56 ;
     RECT  30.125 49.344 30.467 49.368 ;
     RECT  30.373 51.696 30.625 51.72 ;
     RECT  29.704 39.552 30.809 39.768 ;
     RECT  30.625 50.736 30.899 51.72 ;
     RECT  30.899 51.696 31.331 51.72 ;
     RECT  29.704 37.584 34.808 37.608 ;
     RECT  30.809 39.552 34.808 39.576 ;
     RECT  34.808 2.148 34.912 49.692 ;
     RECT  34.912 2.418 35.104 49.422 ;
     RECT  35.104 37.584 35.219 37.608 ;
     RECT  35.104 39.552 35.219 39.576 ;
     RECT  35.104 35.328 36.497 35.352 ;
     RECT  36.529 34.896 40.208 34.92 ;
     RECT  40.208 2.148 40.312 49.692 ;
     RECT  40.312 2.418 40.504 49.422 ;
     RECT  42.332 26.304 42.373 26.328 ;
     RECT  42.373 26.064 42.419 26.328 ;
     RECT  40.504 34.896 42.419 34.92 ;
     RECT  42.419 26.064 43.949 26.088 ;
     RECT  44.953 25.728 45.608 25.752 ;
     RECT  45.608 2.148 45.712 49.692 ;
     RECT  45.712 2.418 45.904 49.422 ;
     RECT  45.904 25.728 46.739 26.232 ;
     RECT  46.739 26.208 47.225 26.232 ;
     RECT  50.677 25.008 51.804 26.76 ;
    LAYER M5 ;
     RECT  2.4 2.137 2.52 2.151 ;
     RECT  7.8 2.137 7.92 2.151 ;
     RECT  13.2 2.137 13.32 2.151 ;
     RECT  18.6 2.137 18.72 2.151 ;
     RECT  24 2.137 24.12 2.151 ;
     RECT  29.4 2.137 29.52 2.151 ;
     RECT  34.8 2.137 34.92 2.151 ;
     RECT  40.2 2.137 40.32 2.151 ;
     RECT  45.6 2.137 45.72 2.151 ;
     RECT  45.6 2.151 45.912 25.717 ;
     RECT  45.6 25.717 46.728 26.243 ;
     RECT  42.384 26.053 42.408 34.931 ;
     RECT  34.8 2.151 35.112 35.317 ;
     RECT  21.888 27.301 21.912 38.197 ;
     RECT  21.888 38.197 22.2 38.243 ;
     RECT  34.8 35.317 35.208 39.587 ;
     RECT  22.176 38.243 22.2 47.891 ;
     RECT  24 2.151 24.312 49.333 ;
     RECT  29.4 2.151 29.712 49.333 ;
     RECT  20.496 37.573 20.52 49.477 ;
     RECT  23.088 49.333 24.312 49.477 ;
     RECT  20.496 49.477 21.384 49.525 ;
     RECT  23.088 49.477 25.272 49.525 ;
     RECT  27.408 49.477 27.432 49.525 ;
     RECT  29.4 49.333 30.456 49.525 ;
     RECT  2.4 2.151 2.712 49.689 ;
     RECT  7.8 2.151 8.112 49.689 ;
     RECT  13.2 2.151 13.512 49.689 ;
     RECT  18.6 2.151 18.912 49.689 ;
     RECT  34.8 39.587 35.112 49.689 ;
     RECT  40.2 2.151 40.512 49.689 ;
     RECT  45.6 26.243 45.912 49.689 ;
     RECT  2.4 49.689 2.52 49.703 ;
     RECT  7.8 49.689 7.92 49.703 ;
     RECT  13.2 49.689 13.32 49.703 ;
     RECT  18.6 49.689 18.72 49.703 ;
     RECT  34.8 49.689 34.92 49.703 ;
     RECT  40.2 49.689 40.32 49.703 ;
     RECT  45.6 49.689 45.72 49.703 ;
     RECT  20.496 49.525 30.456 50.725 ;
     RECT  20.496 50.725 30.888 51.685 ;
     RECT  20.496 51.685 31.32 51.792 ;
     RECT  20.52 37.573 21.888 38.243 ;
  END
END dsfd_vm_static_read_v7
END LIBRARY
